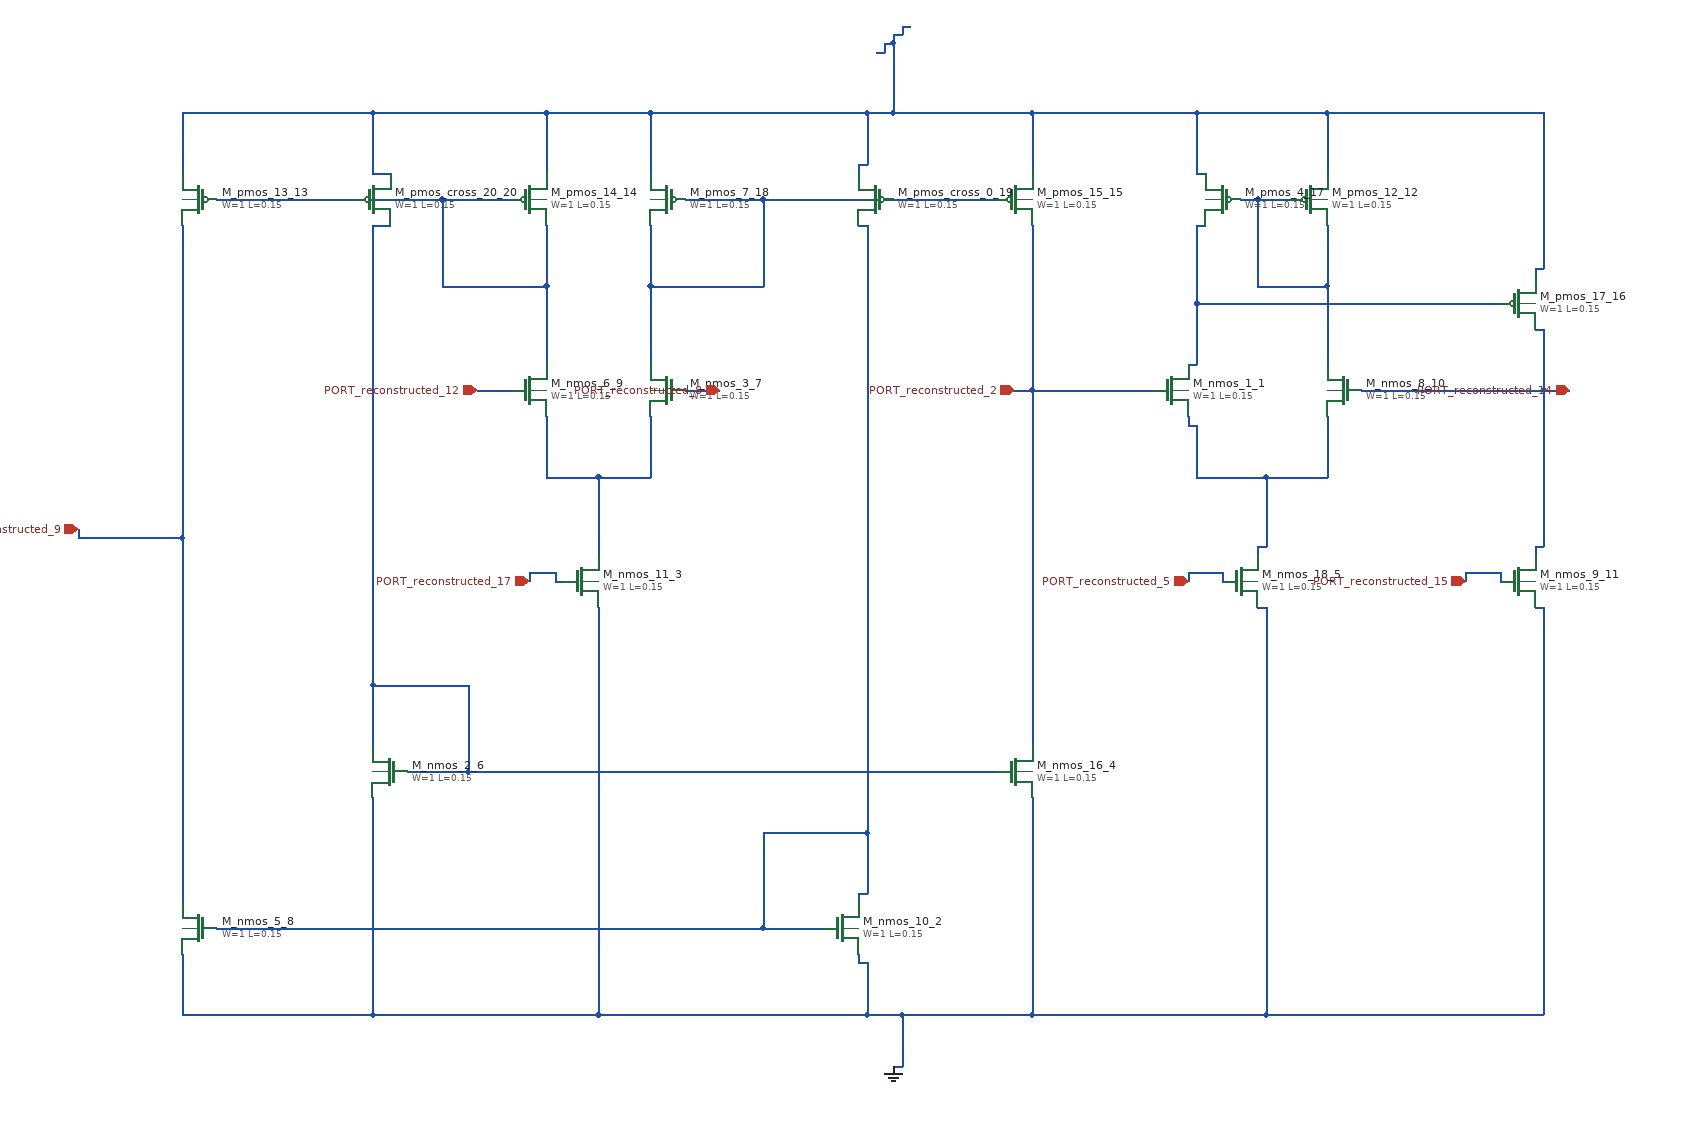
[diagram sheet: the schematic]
v {xschem version=3.4.8 file_version=1.2}
G {}
K {}
V {}
S {}
E {}
C {devices/gnd.sym} 1040 1280 0 0 {name="l_gnd_19_0" lab="GND"}
C {sky130_fd_pr/nfet3_01v8.sym} 1360 500 0 0 {name="M_nmos_1_1"
W=1
L=0.15
body=GND
nf=1
mult=1
ad="expr('int((@nf + 1)/2) * @W / @nf * 0.29')"
pd="expr('2*int((@nf + 1)/2) * (@W / @nf + 0.29)')"
as="expr('int((@nf + 2)/2) * @W / @nf * 0.29')"
ps="expr('2*int((@nf + 2)/2) * (@W / @nf + 0.29)')"
nrd="expr('0.29 / @W ')" nrs="expr('0.29 / @W ')"
sa=0 sb=0 sd=0
model=nfet_01v8
spiceprefix=X
}
C {sky130_fd_pr/nfet3_01v8.sym} 980 1120 0 0 {name="M_nmos_10_2"
W=1
L=0.15
body=GND
nf=1
mult=1
ad="expr('int((@nf + 1)/2) * @W / @nf * 0.29')"
pd="expr('2*int((@nf + 1)/2) * (@W / @nf + 0.29)')"
as="expr('int((@nf + 2)/2) * @W / @nf * 0.29')"
ps="expr('2*int((@nf + 2)/2) * (@W / @nf + 0.29)')"
nrd="expr('0.29 / @W ')" nrs="expr('0.29 / @W ')"
sa=0 sb=0 sd=0
model=nfet_01v8
spiceprefix=X
}
C {sky130_fd_pr/nfet3_01v8.sym} 680 720 0 0 {name="M_nmos_11_3"
W=1
L=0.15
body=GND
nf=1
mult=1
ad="expr('int((@nf + 1)/2) * @W / @nf * 0.29')"
pd="expr('2*int((@nf + 1)/2) * (@W / @nf + 0.29)')"
as="expr('int((@nf + 2)/2) * @W / @nf * 0.29')"
ps="expr('2*int((@nf + 2)/2) * (@W / @nf + 0.29)')"
nrd="expr('0.29 / @W ')" nrs="expr('0.29 / @W ')"
sa=0 sb=0 sd=0
model=nfet_01v8
spiceprefix=X
}
C {sky130_fd_pr/nfet3_01v8.sym} 1180 940 0 0 {name="M_nmos_16_4"
W=1
L=0.15
body=GND
nf=1
mult=1
ad="expr('int((@nf + 1)/2) * @W / @nf * 0.29')"
pd="expr('2*int((@nf + 1)/2) * (@W / @nf + 0.29)')"
as="expr('int((@nf + 2)/2) * @W / @nf * 0.29')"
ps="expr('2*int((@nf + 2)/2) * (@W / @nf + 0.29)')"
nrd="expr('0.29 / @W ')" nrs="expr('0.29 / @W ')"
sa=0 sb=0 sd=0
model=nfet_01v8
spiceprefix=X
}
C {sky130_fd_pr/nfet3_01v8.sym} 1440 720 0 0 {name="M_nmos_18_5"
W=1
L=0.15
body=GND
nf=1
mult=1
ad="expr('int((@nf + 1)/2) * @W / @nf * 0.29')"
pd="expr('2*int((@nf + 1)/2) * (@W / @nf + 0.29)')"
as="expr('int((@nf + 2)/2) * @W / @nf * 0.29')"
ps="expr('2*int((@nf + 2)/2) * (@W / @nf + 0.29)')"
nrd="expr('0.29 / @W ')" nrs="expr('0.29 / @W ')"
sa=0 sb=0 sd=0
model=nfet_01v8
spiceprefix=X
}
C {sky130_fd_pr/nfet3_01v8.sym} 460 940 0 1 {name="M_nmos_2_6"
W=1
L=0.15
body=GND
nf=1
mult=1
ad="expr('int((@nf + 1)/2) * @W / @nf * 0.29')"
pd="expr('2*int((@nf + 1)/2) * (@W / @nf + 0.29)')"
as="expr('int((@nf + 2)/2) * @W / @nf * 0.29')"
ps="expr('2*int((@nf + 2)/2) * (@W / @nf + 0.29)')"
nrd="expr('0.29 / @W ')" nrs="expr('0.29 / @W ')"
sa=0 sb=0 sd=0
model=nfet_01v8
spiceprefix=X
}
C {sky130_fd_pr/nfet3_01v8.sym} 780 500 0 1 {name="M_nmos_3_7"
W=1
L=0.15
body=GND
nf=1
mult=1
ad="expr('int((@nf + 1)/2) * @W / @nf * 0.29')"
pd="expr('2*int((@nf + 1)/2) * (@W / @nf + 0.29)')"
as="expr('int((@nf + 2)/2) * @W / @nf * 0.29')"
ps="expr('2*int((@nf + 2)/2) * (@W / @nf + 0.29)')"
nrd="expr('0.29 / @W ')" nrs="expr('0.29 / @W ')"
sa=0 sb=0 sd=0
model=nfet_01v8
spiceprefix=X
}
C {sky130_fd_pr/nfet3_01v8.sym} 240 1120 0 1 {name="M_nmos_5_8"
W=1
L=0.15
body=GND
nf=1
mult=1
ad="expr('int((@nf + 1)/2) * @W / @nf * 0.29')"
pd="expr('2*int((@nf + 1)/2) * (@W / @nf + 0.29)')"
as="expr('int((@nf + 2)/2) * @W / @nf * 0.29')"
ps="expr('2*int((@nf + 2)/2) * (@W / @nf + 0.29)')"
nrd="expr('0.29 / @W ')" nrs="expr('0.29 / @W ')"
sa=0 sb=0 sd=0
model=nfet_01v8
spiceprefix=X
}
C {sky130_fd_pr/nfet3_01v8.sym} 620 500 0 0 {name="M_nmos_6_9"
W=1
L=0.15
body=GND
nf=1
mult=1
ad="expr('int((@nf + 1)/2) * @W / @nf * 0.29')"
pd="expr('2*int((@nf + 1)/2) * (@W / @nf + 0.29)')"
as="expr('int((@nf + 2)/2) * @W / @nf * 0.29')"
ps="expr('2*int((@nf + 2)/2) * (@W / @nf + 0.29)')"
nrd="expr('0.29 / @W ')" nrs="expr('0.29 / @W ')"
sa=0 sb=0 sd=0
model=nfet_01v8
spiceprefix=X
}
C {sky130_fd_pr/nfet3_01v8.sym} 1560 500 0 1 {name="M_nmos_8_10"
W=1
L=0.15
body=GND
nf=1
mult=1
ad="expr('int((@nf + 1)/2) * @W / @nf * 0.29')"
pd="expr('2*int((@nf + 1)/2) * (@W / @nf + 0.29)')"
as="expr('int((@nf + 2)/2) * @W / @nf * 0.29')"
ps="expr('2*int((@nf + 2)/2) * (@W / @nf + 0.29)')"
nrd="expr('0.29 / @W ')" nrs="expr('0.29 / @W ')"
sa=0 sb=0 sd=0
model=nfet_01v8
spiceprefix=X
}
C {sky130_fd_pr/nfet3_01v8.sym} 1760 720 0 0 {name="M_nmos_9_11"
W=1
L=0.15
body=GND
nf=1
mult=1
ad="expr('int((@nf + 1)/2) * @W / @nf * 0.29')"
pd="expr('2*int((@nf + 1)/2) * (@W / @nf + 0.29)')"
as="expr('int((@nf + 2)/2) * @W / @nf * 0.29')"
ps="expr('2*int((@nf + 2)/2) * (@W / @nf + 0.29)')"
nrd="expr('0.29 / @W ')" nrs="expr('0.29 / @W ')"
sa=0 sb=0 sd=0
model=nfet_01v8
spiceprefix=X
}
C {sky130_fd_pr/pfet3_01v8.sym} 1520 280 0 0 {name="M_pmos_12_12"
W=1
L=0.15
body=VDD
nf=1
mult=1
ad="expr('int((@nf + 1)/2) * @W / @nf * 0.29')"
pd="expr('2*int((@nf + 1)/2) * (@W / @nf + 0.29)')"
as="expr('int((@nf + 2)/2) * @W / @nf * 0.29')"
ps="expr('2*int((@nf + 2)/2) * (@W / @nf + 0.29)')"
nrd="expr('0.29 / @W ')" nrs="expr('0.29 / @W ')"
sa=0 sb=0 sd=0
model=pfet_01v8
spiceprefix=X
}
C {sky130_fd_pr/pfet3_01v8.sym} 240 280 0 1 {name="M_pmos_13_13"
W=1
L=0.15
body=VDD
nf=1
mult=1
ad="expr('int((@nf + 1)/2) * @W / @nf * 0.29')"
pd="expr('2*int((@nf + 1)/2) * (@W / @nf + 0.29)')"
as="expr('int((@nf + 2)/2) * @W / @nf * 0.29')"
ps="expr('2*int((@nf + 2)/2) * (@W / @nf + 0.29)')"
nrd="expr('0.29 / @W ')" nrs="expr('0.29 / @W ')"
sa=0 sb=0 sd=0
model=pfet_01v8
spiceprefix=X
}
C {sky130_fd_pr/pfet3_01v8.sym} 620 280 0 0 {name="M_pmos_14_14"
W=1
L=0.15
body=VDD
nf=1
mult=1
ad="expr('int((@nf + 1)/2) * @W / @nf * 0.29')"
pd="expr('2*int((@nf + 1)/2) * (@W / @nf + 0.29)')"
as="expr('int((@nf + 2)/2) * @W / @nf * 0.29')"
ps="expr('2*int((@nf + 2)/2) * (@W / @nf + 0.29)')"
nrd="expr('0.29 / @W ')" nrs="expr('0.29 / @W ')"
sa=0 sb=0 sd=0
model=pfet_01v8
spiceprefix=X
}
C {sky130_fd_pr/pfet3_01v8.sym} 1180 280 0 0 {name="M_pmos_15_15"
W=1
L=0.15
body=VDD
nf=1
mult=1
ad="expr('int((@nf + 1)/2) * @W / @nf * 0.29')"
pd="expr('2*int((@nf + 1)/2) * (@W / @nf + 0.29)')"
as="expr('int((@nf + 2)/2) * @W / @nf * 0.29')"
ps="expr('2*int((@nf + 2)/2) * (@W / @nf + 0.29)')"
nrd="expr('0.29 / @W ')" nrs="expr('0.29 / @W ')"
sa=0 sb=0 sd=0
model=pfet_01v8
spiceprefix=X
}
C {sky130_fd_pr/pfet3_01v8.sym} 1760 400 0 0 {name="M_pmos_17_16"
W=1
L=0.15
body=VDD
nf=1
mult=1
ad="expr('int((@nf + 1)/2) * @W / @nf * 0.29')"
pd="expr('2*int((@nf + 1)/2) * (@W / @nf + 0.29)')"
as="expr('int((@nf + 2)/2) * @W / @nf * 0.29')"
ps="expr('2*int((@nf + 2)/2) * (@W / @nf + 0.29)')"
nrd="expr('0.29 / @W ')" nrs="expr('0.29 / @W ')"
sa=0 sb=0 sd=0
model=pfet_01v8
spiceprefix=X
}
C {sky130_fd_pr/pfet3_01v8.sym} 1420 280 0 1 {name="M_pmos_4_17"
W=1
L=0.15
body=VDD
nf=1
mult=1
ad="expr('int((@nf + 1)/2) * @W / @nf * 0.29')"
pd="expr('2*int((@nf + 1)/2) * (@W / @nf + 0.29)')"
as="expr('int((@nf + 2)/2) * @W / @nf * 0.29')"
ps="expr('2*int((@nf + 2)/2) * (@W / @nf + 0.29)')"
nrd="expr('0.29 / @W ')" nrs="expr('0.29 / @W ')"
sa=0 sb=0 sd=0
model=pfet_01v8
spiceprefix=X
}
C {sky130_fd_pr/pfet3_01v8.sym} 780 280 0 1 {name="M_pmos_7_18"
W=1
L=0.15
body=VDD
nf=1
mult=1
ad="expr('int((@nf + 1)/2) * @W / @nf * 0.29')"
pd="expr('2*int((@nf + 1)/2) * (@W / @nf + 0.29)')"
as="expr('int((@nf + 2)/2) * @W / @nf * 0.29')"
ps="expr('2*int((@nf + 2)/2) * (@W / @nf + 0.29)')"
nrd="expr('0.29 / @W ')" nrs="expr('0.29 / @W ')"
sa=0 sb=0 sd=0
model=pfet_01v8
spiceprefix=X
}
C {sky130_fd_pr/pfet3_01v8.sym} 1020 280 0 1 {name="M_pmos_cross_0_19"
W=1
L=0.15
body=VDD
nf=1
mult=1
ad="expr('int((@nf + 1)/2) * @W / @nf * 0.29')"
pd="expr('2*int((@nf + 1)/2) * (@W / @nf + 0.29)')"
as="expr('int((@nf + 2)/2) * @W / @nf * 0.29')"
ps="expr('2*int((@nf + 2)/2) * (@W / @nf + 0.29)')"
nrd="expr('0.29 / @W ')" nrs="expr('0.29 / @W ')"
sa=0 sb=0 sd=0
model=pfet_01v8
spiceprefix=X
}
C {sky130_fd_pr/pfet3_01v8.sym} 440 280 0 0 {name="M_pmos_cross_20_20"
W=1
L=0.15
body=VDD
nf=1
mult=1
ad="expr('int((@nf + 1)/2) * @W / @nf * 0.29')"
pd="expr('2*int((@nf + 1)/2) * (@W / @nf + 0.29)')"
as="expr('int((@nf + 2)/2) * @W / @nf * 0.29')"
ps="expr('2*int((@nf + 2)/2) * (@W / @nf + 0.29)')"
nrd="expr('0.29 / @W ')" nrs="expr('0.29 / @W ')"
sa=0 sb=0 sd=0
model=pfet_01v8
spiceprefix=X
}
C {devices/ipin.sym} 100 660 0 0 {name="p_port_21_21" lab="PORT_reconstructed_9"}
C {devices/ipin.sym} 620 720 0 0 {name="p_port_22_22" lab="PORT_reconstructed_17"}
C {devices/ipin.sym} 840 500 0 0 {name="p_port_23_23" lab="PORT_reconstructed_8"}
C {devices/ipin.sym} 1820 500 0 0 {name="p_port_24_24" lab="PORT_reconstructed_14"}
C {devices/ipin.sym} 1700 720 0 0 {name="p_port_25_25" lab="PORT_reconstructed_15"}
C {devices/ipin.sym} 1380 720 0 0 {name="p_port_26_26" lab="PORT_reconstructed_5"}
C {devices/ipin.sym} 560 500 0 0 {name="p_port_27_27" lab="PORT_reconstructed_12"}
C {devices/ipin.sym} 1180 500 0 0 {name="p_port_29_28" lab="PORT_reconstructed_2"}
N 1040 1280 1050 1280 {}
N 220 1220 440 1220 {}
N 440 1220 700 1220 {}
N 700 1220 1010 1220 {}
N 1010 1220 1050 1220 {}
N 1050 1220 1200 1220 {}
N 1200 1220 1470 1220 {}
N 1470 1220 1790 1220 {}
N 1000 1160 1010 1160 {}
N 1460 750 1470 750 {}
N 1780 750 1790 750 {}
N 220 1220 220 1150 {}
N 440 1220 440 970 {}
N 700 1220 700 750 {}
N 1000 1160 1000 1150 {}
N 1010 1220 1010 1160 {}
N 1050 1280 1050 1220 {}
N 1200 1220 1200 970 {}
N 1470 1220 1470 750 {}
N 1790 1220 1790 750 {}
N 1380 470 1390 470 {}
N 1390 400 1740 400 {}
N 1740 400 1750 400 {}
N 1390 310 1400 310 {}
N 1390 470 1390 400 {}
N 1390 400 1390 310 {}
N 260 1120 890 1120 {}
N 890 1120 960 1120 {}
N 1000 1080 1010 1080 {}
N 890 1010 1010 1010 {}
N 1000 310 1010 310 {}
N 890 1120 890 1010 {}
N 1000 1090 1000 1080 {}
N 1010 1080 1010 1010 {}
N 1010 1010 1010 310 {}
N 520 380 640 380 {}
N 260 280 420 280 {}
N 420 280 520 280 {}
N 520 280 600 280 {}
N 520 380 520 280 {}
N 640 470 640 380 {}
N 640 380 640 310 {}
N 560 500 600 500 {}
N 1460 380 1540 380 {}
N 1440 280 1460 280 {}
N 1460 280 1500 280 {}
N 1460 380 1460 280 {}
N 1540 470 1540 380 {}
N 1540 380 1540 310 {}
N 1780 680 1790 680 {}
N 1580 500 1790 500 {}
N 1790 500 1820 500 {}
N 1780 430 1790 430 {}
N 1780 690 1780 680 {}
N 1790 680 1790 500 {}
N 1790 500 1790 430 {}
N 1700 710 1740 710 {}
N 1700 720 1700 710 {}
N 1740 720 1740 710 {}
N 1780 360 1790 360 {}
N 440 250 460 250 {}
N 1390 250 1400 250 {}
N 1000 240 1010 240 {}
N 220 180 440 180 {}
N 440 180 640 180 {}
N 640 180 760 180 {}
N 760 180 1010 180 {}
N 1010 180 1040 180 {}
N 1040 180 1200 180 {}
N 1200 180 1390 180 {}
N 1390 180 1540 180 {}
N 1540 180 1790 180 {}
N 1020 110 1030 110 {}
N 1030 100 1040 100 {}
N 1040 90 1050 90 {}
N 1050 80 1060 80 {}
N 220 250 220 180 {}
N 440 250 440 180 {}
N 640 250 640 180 {}
N 760 250 760 180 {}
N 1000 250 1000 240 {}
N 1010 240 1010 180 {}
N 1030 110 1030 100 {}
N 1040 180 1040 100 {}
N 1040 100 1040 90 {}
N 1050 90 1050 80 {}
N 1200 250 1200 180 {}
N 1390 250 1390 180 {}
N 1540 250 1540 180 {}
N 1780 370 1780 360 {}
N 1790 360 1790 180 {}
N 650 720 660 720 {}
N 620 710 650 710 {}
N 620 720 620 710 {}
N 650 720 650 710 {}
N 1180 500 1200 500 {}
N 1200 500 1340 500 {}
N 1340 500 1350 500 {}
N 1200 910 1200 500 {}
N 1200 500 1200 310 {}
N 480 940 550 940 {}
N 550 940 1160 940 {}
N 440 840 550 840 {}
N 440 310 460 310 {}
N 440 910 440 840 {}
N 440 840 440 310 {}
N 550 940 550 840 {}
N 1460 680 1470 680 {}
N 1390 600 1470 600 {}
N 1470 600 1540 600 {}
N 1380 540 1390 540 {}
N 1380 540 1380 530 {}
N 1390 600 1390 540 {}
N 1460 690 1460 680 {}
N 1470 680 1470 600 {}
N 1540 600 1540 530 {}
N 1380 710 1420 710 {}
N 1380 720 1380 710 {}
N 1420 720 1420 710 {}
N 640 600 700 600 {}
N 700 600 760 600 {}
N 640 600 640 530 {}
N 700 690 700 600 {}
N 760 600 760 530 {}
N 760 380 890 380 {}
N 800 280 890 280 {}
N 890 280 1040 280 {}
N 1040 280 1160 280 {}
N 760 470 760 380 {}
N 760 380 760 310 {}
N 890 380 890 280 {}
N 800 500 840 500 {}
N 100 670 220 670 {}
N 100 670 100 660 {}
N 220 1090 220 670 {}
N 220 670 220 310 {}
